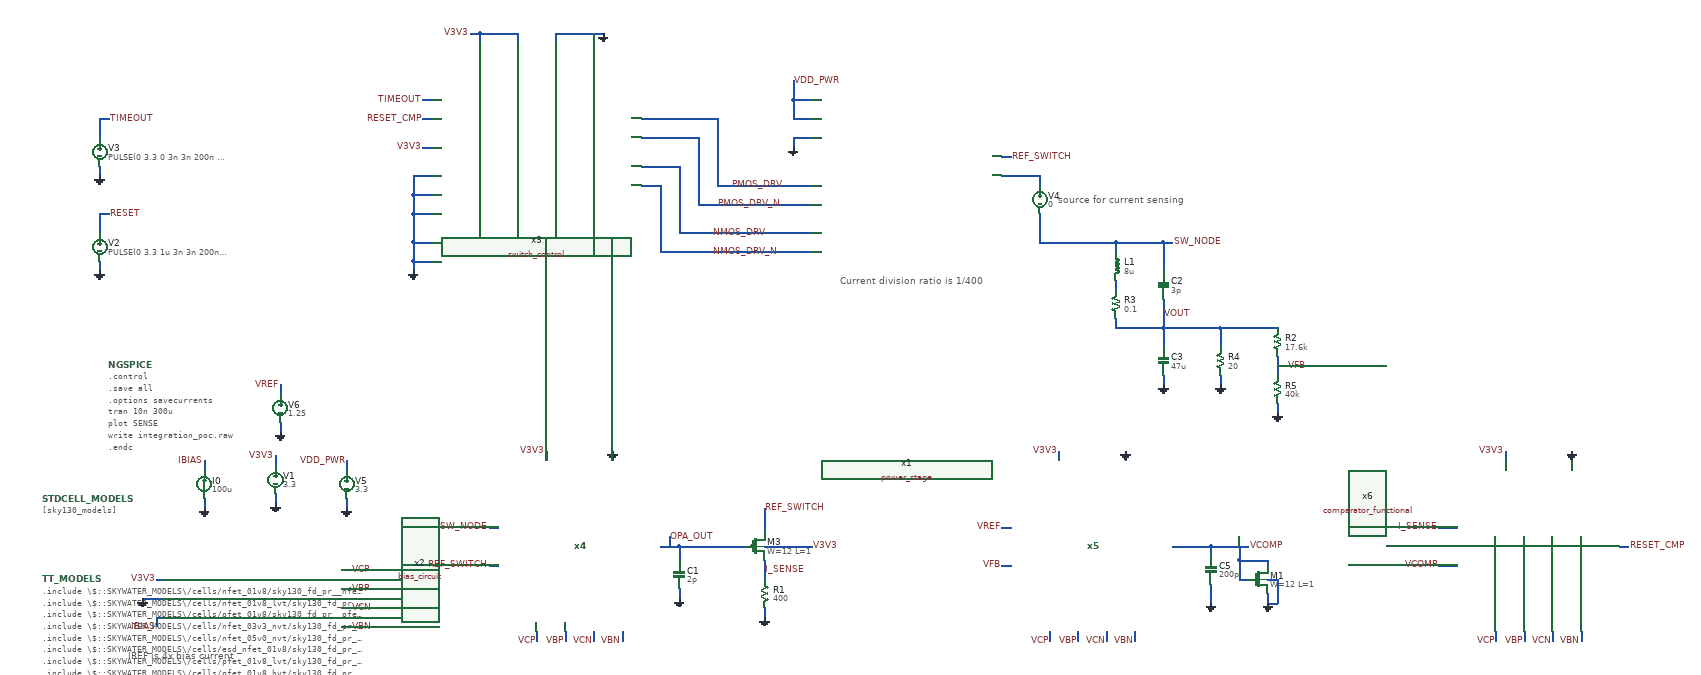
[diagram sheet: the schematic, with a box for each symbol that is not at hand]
v {xschem version=2.9.9 file_version=1.2 }
G {}
K {}
V {}
S {}
E {}
T {IREF is 4x bias current} 240 -100 0 0 0.4 0.4 {}
T {Current division ratio is 1/400} 1740 -890 0 0 0.4 0.4 {}
T {source for current sensing} 2200 -1060 0 0 0.4 0.4 {}
N 550 -510 550 -490 { lab=V3V3}
N 550 -430 550 -410 { lab=GND}
N 400 -420 400 -400 { lab=GND}
N 400 -500 400 -480 { lab=IBIAS}
N 270 -210 310 -210 { lab=GND}
N 300 -250 310 -250 { lab=V3V3}
N 300 -170 310 -170 { lab=IBIAS}
N 300 -170 300 -150 { lab=IBIAS}
N 690 -270 710 -270 { lab=VCP}
N 690 -230 710 -230 { lab=VBP}
N 690 -190 710 -190 { lab=VCN}
N 690 -150 710 -150 { lab=VBN}
N 1260 -520 1260 -500 { lab=GND}
N 1120 -520 1120 -500 { lab=V3V3}
N 1000 -360 1020 -360 { lab=SW_NODE}
N 1000 -280 1020 -280 { lab=REF_SWITCH}
N 1100 -140 1100 -120 { lab=VCP}
N 1160 -140 1160 -120 { lab=VBP}
N 1220 -140 1220 -120 { lab=VCN}
N 1280 -140 1280 -120 { lab=VBN}
N 1360 -320 1400 -320 { lab=OPA_OUT}
N 1580 -190 1580 -170 { lab=GND}
N 1400 -230 1400 -210 { lab=GND}
N 1400 -320 1400 -290 { lab=OPA_OUT}
N 1320 -1080 1360 -1080 { lab=NMOS_DRV_N}
N 1360 -1080 1360 -940 { lab=NMOS_DRV_N}
N 1360 -940 1680 -940 { lab=NMOS_DRV_N}
N 1320 -1120 1400 -1120 { lab=NMOS_DRV}
N 1400 -1120 1400 -980 { lab=NMOS_DRV}
N 1400 -980 1680 -980 { lab=NMOS_DRV}
N 1320 -1180 1440 -1180 { lab=PMOS_DRV_N}
N 1440 -1180 1440 -1040 { lab=PMOS_DRV_N}
N 1440 -1040 1680 -1040 { lab=PMOS_DRV_N}
N 1320 -1220 1480 -1220 { lab=PMOS_DRV}
N 1480 -1220 1480 -1080 { lab=PMOS_DRV}
N 1480 -1080 1680 -1080 { lab=PMOS_DRV}
N 1640 -1180 1680 -1180 { lab=GND}
N 1640 -1180 1640 -1160 { lab=GND}
N 1640 -1220 1680 -1220 { lab=VDD_PWR}
N 1640 -1260 1640 -1220 { lab=VDD_PWR}
N 1640 -1260 1680 -1260 { lab=VDD_PWR}
N 1640 -1300 1640 -1260 { lab=VDD_PWR}
N 2420 -940 2420 -900 { lab=SW_NODE}
N 2420 -960 2420 -940 { lab=SW_NODE}
N 2320 -960 2420 -960 { lab=SW_NODE}
N 2320 -960 2320 -940 { lab=SW_NODE}
N 2320 -880 2320 -860 { lab=#net1}
N 2420 -840 2420 -780 { lab=VOUT}
N 2320 -780 2420 -780 { lab=VOUT}
N 2320 -800 2320 -780 { lab=VOUT}
N 180 -1120 180 -1100 { lab=GND}
N 180 -1200 180 -1180 { lab=TIMEOUT}
N 180 -1220 200 -1220 { lab=TIMEOUT}
N 180 -1220 180 -1200 { lab=TIMEOUT}
N 2420 -680 2420 -660 { lab=GND}
N 2420 -780 2420 -740 { lab=VOUT}
N 2540 -680 2540 -660 { lab=GND}
N 2420 -780 2540 -780 { lab=VOUT}
N 2540 -770 2540 -740 { lab=VOUT}
N 2540 -780 2540 -770 { lab=VOUT}
N 2220 -960 2320 -960 { lab=SW_NODE}
N 2080 -1140 2100 -1140 { lab=REF_SWITCH}
N 840 -920 880 -920 { lab=GND}
N 840 -920 840 -910 { lab=GND}
N 840 -910 840 -900 { lab=GND}
N 840 -960 880 -960 { lab=GND}
N 840 -960 840 -920 { lab=GND}
N 840 -1020 880 -1020 { lab=GND}
N 840 -1020 840 -960 { lab=GND}
N 840 -1060 880 -1060 { lab=GND}
N 840 -1060 840 -1020 { lab=GND}
N 840 -1100 880 -1100 { lab=GND}
N 840 -1100 840 -1060 { lab=GND}
N 860 -1160 880 -1160 { lab=V3V3}
N 960 -1400 980 -1400 { lab=V3V3}
N 980 -1400 980 -1380 { lab=V3V3}
N 980 -1400 1060 -1400 { lab=V3V3}
N 1060 -1400 1060 -1380 { lab=V3V3}
N 1140 -1400 1140 -1380 { lab=GND}
N 1140 -1400 1240 -1400 { lab=GND}
N 1220 -1400 1220 -1380 { lab=GND}
N 860 -1260 880 -1260 { lab=TIMEOUT}
N 1580 -290 1580 -270 { lab=I_SENSE}
N 1580 -270 1580 -250 { lab=I_SENSE}
N 1380 -340 1380 -320 { lab=OPA_OUT}
N 2420 -960 2440 -960 { lab=SW_NODE}
N 1400 -320 1540 -320 { lab=OPA_OUT}
N 1580 -400 1580 -350 { lab=REF_SWITCH}
N 180 -920 180 -900 { lab=GND}
N 180 -1000 180 -980 { lab=RESET}
N 180 -1020 200 -1020 { lab=RESET}
N 180 -1020 180 -1000 { lab=RESET}
N 2080 -1100 2160 -1100 { lab=#net2}
N 2160 -1100 2160 -1080 { lab=#net2}
N 2160 -1020 2160 -960 { lab=SW_NODE}
N 2160 -960 2220 -960 { lab=SW_NODE}
N 860 -1220 880 -1220 { lab=RESET_CMP}
N 1580 -320 1680 -320 { lab=V3V3}
N 700 -500 700 -480 { lab=VDD_PWR}
N 700 -420 700 -400 { lab=GND}
N 2180 -140 2180 -120 { lab=VCP}
N 2240 -140 2240 -120 { lab=VBP}
N 2300 -140 2300 -120 { lab=VCN}
N 2360 -140 2360 -120 { lab=VBN}
N 2340 -520 2340 -500 { lab=GND}
N 2200 -520 2200 -500 { lab=V3V3}
N 560 -660 560 -640 { lab=VREF}
N 560 -580 560 -560 { lab=GND}
N 2660 -720 2660 -680 { lab=VFB}
N 2660 -620 2660 -600 { lab=GND}
N 2540 -780 2660 -780 { lab=VOUT}
N 2660 -700 2680 -700 { lab=VFB}
N 2080 -360 2100 -360 { lab=VREF}
N 2080 -280 2100 -280 { lab=VFB}
N 2520 -240 2520 -200 { lab=GND}
N 2440 -320 2520 -320 { lab=VCOMP}
N 2520 -320 2520 -300 { lab=VCOMP}
N 2520 -320 2600 -320 { lab=VCOMP}
N 3120 -140 3120 -120 { lab=VCP}
N 3180 -140 3180 -120 { lab=VBP}
N 3240 -140 3240 -120 { lab=VCN}
N 3300 -140 3300 -120 { lab=VBN}
N 3000 -280 3040 -280 { lab=VCOMP}
N 3000 -360 3040 -360 { lab=I_SENSE}
N 3280 -520 3280 -500 { lab=GND}
N 3140 -520 3140 -500 { lab=V3V3}
N 3380 -320 3400 -320 { lab=RESET_CMP}
N 2640 -220 2640 -200 { lab=GND}
N 2640 -250 2660 -250 { lab=GND}
N 2660 -250 2660 -200 { lab=GND}
N 2640 -200 2660 -200 { lab=GND}
N 2580 -250 2600 -250 { lab=VCOMP}
N 2580 -290 2580 -250 { lab=VCOMP}
N 2580 -290 2640 -290 { lab=VCOMP}
N 2640 -290 2640 -280 { lab=VCOMP}
N 2580 -320 2580 -290 { lab=VCOMP}
C {devices/code_shown.sym} 198.75 -701.875 0 0 {name=NGSPICE
only_toplevel=true
value="

.control
.save all
.options savecurrents
tran 10n 300u
plot SENSE
write integration_poc.raw
.endc
"}
C {devices/code.sym} 60 -420 0 0 {name=STDCELL_MODELS 
only_toplevel=true
place=end
format="tcleval(@value )"
value="[sky130_models]"
name=s1 only_toplevel=false value=blabla}
C {devices/code.sym} 60 -250 0 0 {name=TT_MODELS
only_toplevel=true
format="tcleval( @value )"
value="
.include \\\\$::SKYWATER_MODELS\\\\/cells/nfet_01v8/sky130_fd_pr__nfet_01v8__tt.corner.spice
.include \\\\$::SKYWATER_MODELS\\\\/cells/nfet_01v8_lvt/sky130_fd_pr__nfet_01v8_lvt__tt.corner.spice
.include \\\\$::SKYWATER_MODELS\\\\/cells/pfet_01v8/sky130_fd_pr__pfet_01v8__tt.corner.spice
.include \\\\$::SKYWATER_MODELS\\\\/cells/nfet_03v3_nvt/sky130_fd_pr__nfet_03v3_nvt__tt.corner.spice
.include \\\\$::SKYWATER_MODELS\\\\/cells/nfet_05v0_nvt/sky130_fd_pr__nfet_05v0_nvt__tt.corner.spice
.include \\\\$::SKYWATER_MODELS\\\\/cells/esd_nfet_01v8/sky130_fd_pr__esd_nfet_01v8__tt.corner.spice
.include \\\\$::SKYWATER_MODELS\\\\/cells/pfet_01v8_lvt/sky130_fd_pr__pfet_01v8_lvt__tt.corner.spice
.include \\\\$::SKYWATER_MODELS\\\\/cells/pfet_01v8_hvt/sky130_fd_pr__pfet_01v8_hvt__tt.corner.spice
.include \\\\$::SKYWATER_MODELS\\\\/cells/esd_pfet_g5v0d10v5/sky130_fd_pr__esd_pfet_g5v0d10v5__tt.corner.spice
.include \\\\$::SKYWATER_MODELS\\\\/cells/pfet_g5v0d10v5/sky130_fd_pr__pfet_g5v0d10v5__tt.corner.spice
.include \\\\$::SKYWATER_MODELS\\\\/cells/pfet_g5v0d16v0/sky130_fd_pr__pfet_g5v0d16v0__tt.corner.spice
.include \\\\$::SKYWATER_MODELS\\\\/cells/nfet_g5v0d10v5/sky130_fd_pr__nfet_g5v0d10v5__tt.corner.spice
.include \\\\$::SKYWATER_MODELS\\\\/cells/nfet_g5v0d16v0/sky130_fd_pr__nfet_g5v0d16v0__tt_discrete.corner.spice
.include \\\\$::SKYWATER_MODELS\\\\/cells/esd_nfet_g5v0d10v5/sky130_fd_pr__esd_nfet_g5v0d10v5__tt.corner.spice
.include \\\\$::SKYWATER_MODELS\\\\/models/corners/tt/nonfet.spice
* Mismatch parameters
.include \\\\$::SKYWATER_MODELS\\\\/cells/nfet_01v8/sky130_fd_pr__nfet_01v8__mismatch.corner.spice
.include \\\\$::SKYWATER_MODELS\\\\/cells/pfet_01v8/sky130_fd_pr__pfet_01v8__mismatch.corner.spice
.include \\\\$::SKYWATER_MODELS\\\\/cells/nfet_01v8_lvt/sky130_fd_pr__nfet_01v8_lvt__mismatch.corner.spice
.include \\\\$::SKYWATER_MODELS\\\\/cells/pfet_01v8_lvt/sky130_fd_pr__pfet_01v8_lvt__mismatch.corner.spice
.include \\\\$::SKYWATER_MODELS\\\\/cells/pfet_01v8_hvt/sky130_fd_pr__pfet_01v8_hvt__mismatch.corner.spice
.include \\\\$::SKYWATER_MODELS\\\\/cells/nfet_g5v0d10v5/sky130_fd_pr__nfet_g5v0d10v5__mismatch.corner.spice
.include \\\\$::SKYWATER_MODELS\\\\/cells/pfet_g5v0d10v5/sky130_fd_pr__pfet_g5v0d10v5__mismatch.corner.spice
.include \\\\$::SKYWATER_MODELS\\\\/cells/nfet_05v0_nvt/sky130_fd_pr__nfet_05v0_nvt__mismatch.corner.spice
.include \\\\$::SKYWATER_MODELS\\\\/cells/nfet_03v3_nvt/sky130_fd_pr__nfet_03v3_nvt__mismatch.corner.spice
* Resistor\\\\$::SKYWATER_MODELS\\\\/Capacitor
.include \\\\$::SKYWATER_MODELS\\\\/models/r+c/res_typical__cap_typical.spice
.include \\\\$::SKYWATER_MODELS\\\\/models/r+c/res_typical__cap_typical__lin.spice
* Special cells
.include \\\\$::SKYWATER_MODELS\\\\/models/corners/tt/specialized_cells.spice
* All models
.include \\\\$::SKYWATER_MODELS\\\\/models/all.spice
* Corner
.include \\\\$::SKYWATER_MODELS\\\\/models/corners/tt/rf.spice
"
}
C {devices/vsource.sym} 550 -460 0 0 {name=V1 value=3.3}
C {devices/gnd.sym} 550 -410 0 0 {name=l2 lab=GND}
C {devices/lab_pin.sym} 550 -510 0 0 {name=l3 sig_type=std_logic lab=V3V3
}
C {devices/isource.sym} 400 -450 2 0 {name=I0 value=100u
}
C {devices/gnd.sym} 400 -400 0 0 {name=l1 lab=GND}
C {devices/lab_pin.sym} 400 -500 0 0 {name=l4 sig_type=std_logic lab=IBIAS
}
C {devices/lab_pin.sym} 300 -250 0 0 {name=l5 sig_type=std_logic lab=V3V3
}
C {devices/gnd.sym} 270 -210 1 0 {name=l6 lab=GND}
C {devices/lab_pin.sym} 300 -150 0 0 {name=l7 sig_type=std_logic lab=IBIAS
}
C {devices/lab_pin.sym} 710 -150 2 0 {name=l8 sig_type=std_logic lab=VBN
}
C {devices/lab_pin.sym} 710 -190 2 0 {name=l9 sig_type=std_logic lab=VCN
}
C {devices/lab_pin.sym} 710 -230 2 0 {name=l10 sig_type=std_logic lab=VBP
}
C {devices/lab_pin.sym} 710 -270 2 0 {name=l11 sig_type=std_logic lab=VCP


}
C {devices/lab_pin.sym} 1100 -120 3 0 {name=l12 sig_type=std_logic lab=VCP


}
C {devices/lab_pin.sym} 1160 -120 3 0 {name=l13 sig_type=std_logic lab=VBP
}
C {devices/lab_pin.sym} 1220 -120 3 0 {name=l14 sig_type=std_logic lab=VCN
}
C {devices/lab_pin.sym} 1280 -120 3 0 {name=l15 sig_type=std_logic lab=VBN
}
C {devices/lab_pin.sym} 1120 -520 0 0 {name=l21 sig_type=std_logic lab=V3V3
}
C {devices/gnd.sym} 1260 -520 2 0 {name=l22 lab=GND}
C {design/bias-circuit/bias_circuit.sym} 500 -210 0 0 {name=x2}
C {sky130_fd_pr/pfet_g5v0d10v5.sym} 1560 -320 0 0 {name=M3
L=1
W=12
nf=1
mult=6
ad="'int((nf+1)/2) * W/nf * 0.29'" 
pd="'2*int((nf+1)/2) * (W/nf + 0.29)'"
as="'int((nf+2)/2) * W/nf * 0.29'" 
ps="'2*int((nf+2)/2) * (W/nf + 0.29)'"
nrd="'0.29 / W'" nrs="'0.29 / W'"
sa=0 sb=0 sd=0
model=pfet_g5v0d10v5
spiceprefix=X
}
C {devices/res.sym} 1580 -220 0 0 {name=R1
value=400
footprint=1206
device=resistor
m=1}
C {devices/gnd.sym} 1580 -170 0 0 {name=l31 lab=GND}
C {devices/lab_pin.sym} 1380 -340 2 0 {name=l16 sig_type=std_logic lab=OPA_OUT
}
C {devices/lab_pin.sym} 1580 -270 2 0 {name=l17 sig_type=std_logic lab=I_SENSE
}
C {devices/capa.sym} 1400 -260 0 0 {name=C1
m=1
value=2p
footprint=1206
device="ceramic capacitor"}
C {devices/gnd.sym} 1400 -210 0 0 {name=l18 lab=GND}
C {design/power-stage/power_stage.sym} 1880 -1120 0 0 {name=x1}
C {design/switch-control/switch_control.sym} 1100 -1160 0 0 {name=x3}
C {devices/gnd.sym} 1640 -1160 0 0 {name=l23 lab=GND}
C {devices/lab_pin.sym} 1640 -1300 2 0 {name=l33 sig_type=std_logic lab=VDD_PWR
}
C {devices/ind.sym} 2320 -910 0 0 {name=L1
m=1
value=8u
footprint=1206
device=inductor}
C {devices/res.sym} 2320 -830 2 0 {name=R3
value=0.1
footprint=1206
device=resistor
m=1}
C {devices/capa.sym} 2420 -870 0 0 {name=C2
m=1
value=3p
footprint=1206
device="ceramic capacitor"}
C {devices/vsource.sym} 180 -1150 0 0 {name=V3 value="PULSE(0 3.3 0 3n 3n 200n 2u)"}
C {devices/gnd.sym} 180 -1100 0 0 {name=l36 lab=GND}
C {devices/lab_pin.sym} 200 -1220 2 0 {name=l37 sig_type=std_logic lab=TIMEOUT
}
C {devices/gnd.sym} 840 -900 0 0 {name=l38 lab=GND}
C {devices/capa.sym} 2420 -710 0 0 {name=C3
m=1
value=47u
footprint=1206
device="ceramic capacitor"}
C {devices/gnd.sym} 2420 -660 0 0 {name=l35 lab=GND}
C {devices/res.sym} 2540 -710 2 0 {name=R4
value=20
footprint=1206
device=resistor
m=1}
C {devices/gnd.sym} 2540 -660 0 0 {name=l39 lab=GND}
C {devices/lab_pin.sym} 2100 -1140 2 0 {name=l25 sig_type=std_logic lab=REF_SWITCH
}
C {devices/lab_pin.sym} 860 -1160 0 0 {name=l24 sig_type=std_logic lab=V3V3
}
C {devices/lab_pin.sym} 960 -1400 0 0 {name=l26 sig_type=std_logic lab=V3V3
}
C {devices/gnd.sym} 1240 -1400 3 0 {name=l27 lab=GND}
C {devices/lab_pin.sym} 860 -1260 0 0 {name=l28 sig_type=std_logic lab=TIMEOUT
}
C {devices/lab_pin.sym} 1580 -400 2 0 {name=l29 sig_type=std_logic lab=REF_SWITCH
}
C {devices/lab_pin.sym} 1000 -280 0 0 {name=l19 sig_type=std_logic lab=REF_SWITCH
}
C {devices/lab_pin.sym} 2440 -960 2 0 {name=l20 sig_type=std_logic lab=SW_NODE
}
C {devices/lab_pin.sym} 1000 -360 0 0 {name=l30 sig_type=std_logic lab=SW_NODE
}
C {devices/vsource.sym} 180 -950 0 0 {name=V2 value="PULSE(0 3.3 1u 3n 3n 200n 2u)"}
C {devices/gnd.sym} 180 -900 0 0 {name=l32 lab=GND}
C {devices/lab_pin.sym} 200 -1020 2 0 {name=l34 sig_type=std_logic lab=RESET
}
C {devices/vsource.sym} 2160 -1050 0 0 {name=V4 value=0}
C {devices/lab_pin.sym} 860 -1220 0 0 {name=l40 sig_type=std_logic lab=RESET_CMP
}
C {devices/lab_pin.sym} 1680 -320 2 0 {name=l41 sig_type=std_logic lab=V3V3
}
C {devices/vsource.sym} 700 -450 0 0 {name=V5 value=3.3}
C {devices/gnd.sym} 700 -400 0 0 {name=l42 lab=GND}
C {devices/lab_pin.sym} 700 -500 0 0 {name=l43 sig_type=std_logic lab=VDD_PWR
}
C {design/folded-cascode-n-in/folded_cascode_n_in.sym} 1180 -320 0 0 {name=x4}
C {devices/lab_wire.sym} 1510 -1080 0 1 {name=l44 sig_type=std_logic lab=PMOS_DRV}
C {devices/lab_wire.sym} 1480 -1040 0 1 {name=l45 sig_type=std_logic lab=PMOS_DRV_N}
C {devices/lab_wire.sym} 1470 -980 0 1 {name=l46 sig_type=std_logic lab=NMOS_DRV}
C {devices/lab_wire.sym} 1470 -940 0 1 {name=l47 sig_type=std_logic lab=NMOS_DRV_N}
C {design/folded-cascode-p-in/folded_cascode_p_in.sym} 2260 -320 0 0 {name=x5}
C {devices/lab_pin.sym} 2180 -120 3 0 {name=l48 sig_type=std_logic lab=VCP


}
C {devices/lab_pin.sym} 2240 -120 3 0 {name=l49 sig_type=std_logic lab=VBP
}
C {devices/lab_pin.sym} 2300 -120 3 0 {name=l50 sig_type=std_logic lab=VCN
}
C {devices/lab_pin.sym} 2360 -120 3 0 {name=l51 sig_type=std_logic lab=VBN
}
C {devices/lab_pin.sym} 2200 -520 0 0 {name=l52 sig_type=std_logic lab=V3V3
}
C {devices/gnd.sym} 2340 -520 2 0 {name=l53 lab=GND}
C {devices/vsource.sym} 560 -610 0 0 {name=V6 value=1.25}
C {devices/gnd.sym} 560 -560 0 0 {name=l54 lab=GND}
C {devices/lab_pin.sym} 560 -660 0 0 {name=l55 sig_type=std_logic lab=VREF
}
C {devices/lab_pin.sym} 2080 -360 0 0 {name=l56 sig_type=std_logic lab=VREF
}
C {devices/res.sym} 2660 -750 2 0 {name=R2
value=17.6k
footprint=1206
device=resistor
m=1}
C {devices/lab_pin.sym} 2420 -810 2 0 {name=l57 sig_type=std_logic lab=VOUT
}
C {devices/res.sym} 2660 -650 2 0 {name=R5
value=40k
footprint=1206
device=resistor
m=1}
C {devices/gnd.sym} 2660 -600 0 0 {name=l58 lab=GND}
C {devices/lab_pin.sym} 2680 -700 2 0 {name=l59 sig_type=std_logic lab=VFB
}
C {devices/lab_pin.sym} 2080 -280 0 0 {name=l60 sig_type=std_logic lab=VFB
}
C {devices/capa.sym} 2520 -270 0 0 {name=C5
m=1
value=200p
footprint=1206
device="ceramic capacitor"}
C {devices/gnd.sym} 2520 -200 0 0 {name=l61 lab=GND}
C {devices/lab_pin.sym} 2600 -320 2 0 {name=l62 sig_type=std_logic lab=VCOMP
}
C {design/comparator/comparator_functional.sym} 3200 -320 0 0 {name=x6}
C {devices/lab_pin.sym} 3120 -120 3 0 {name=l63 sig_type=std_logic lab=VCP


}
C {devices/lab_pin.sym} 3180 -120 3 0 {name=l64 sig_type=std_logic lab=VBP
}
C {devices/lab_pin.sym} 3240 -120 3 0 {name=l65 sig_type=std_logic lab=VCN
}
C {devices/lab_pin.sym} 3300 -120 3 0 {name=l66 sig_type=std_logic lab=VBN
}
C {devices/lab_pin.sym} 3000 -280 0 0 {name=l67 sig_type=std_logic lab=VCOMP
}
C {devices/lab_pin.sym} 3000 -360 0 0 {name=l68 sig_type=std_logic lab=I_SENSE
}
C {devices/lab_pin.sym} 3140 -520 0 0 {name=l69 sig_type=std_logic lab=V3V3
}
C {devices/gnd.sym} 3280 -520 2 0 {name=l70 lab=GND}
C {devices/lab_pin.sym} 3400 -320 2 0 {name=l71 sig_type=std_logic lab=RESET_CMP
}
C {sky130_fd_pr/nfet_g5v0d10v5.sym} 2620 -250 0 0 {name=M1
L=1
W=12
nf=1
mult=1
ad="'int((nf+1)/2) * W/nf * 0.29'" 
pd="'2*int((nf+1)/2) * (W/nf + 0.29)'"
as="'int((nf+2)/2) * W/nf * 0.29'" 
ps="'2*int((nf+2)/2) * (W/nf + 0.29)'"
nrd="'0.29 / W'" nrs="'0.29 / W'"
sa=0 sb=0 sd=0
model=nfet_g5v0d10v5
spiceprefix=X
}
C {devices/gnd.sym} 2640 -200 0 0 {name=l72 lab=GND}
